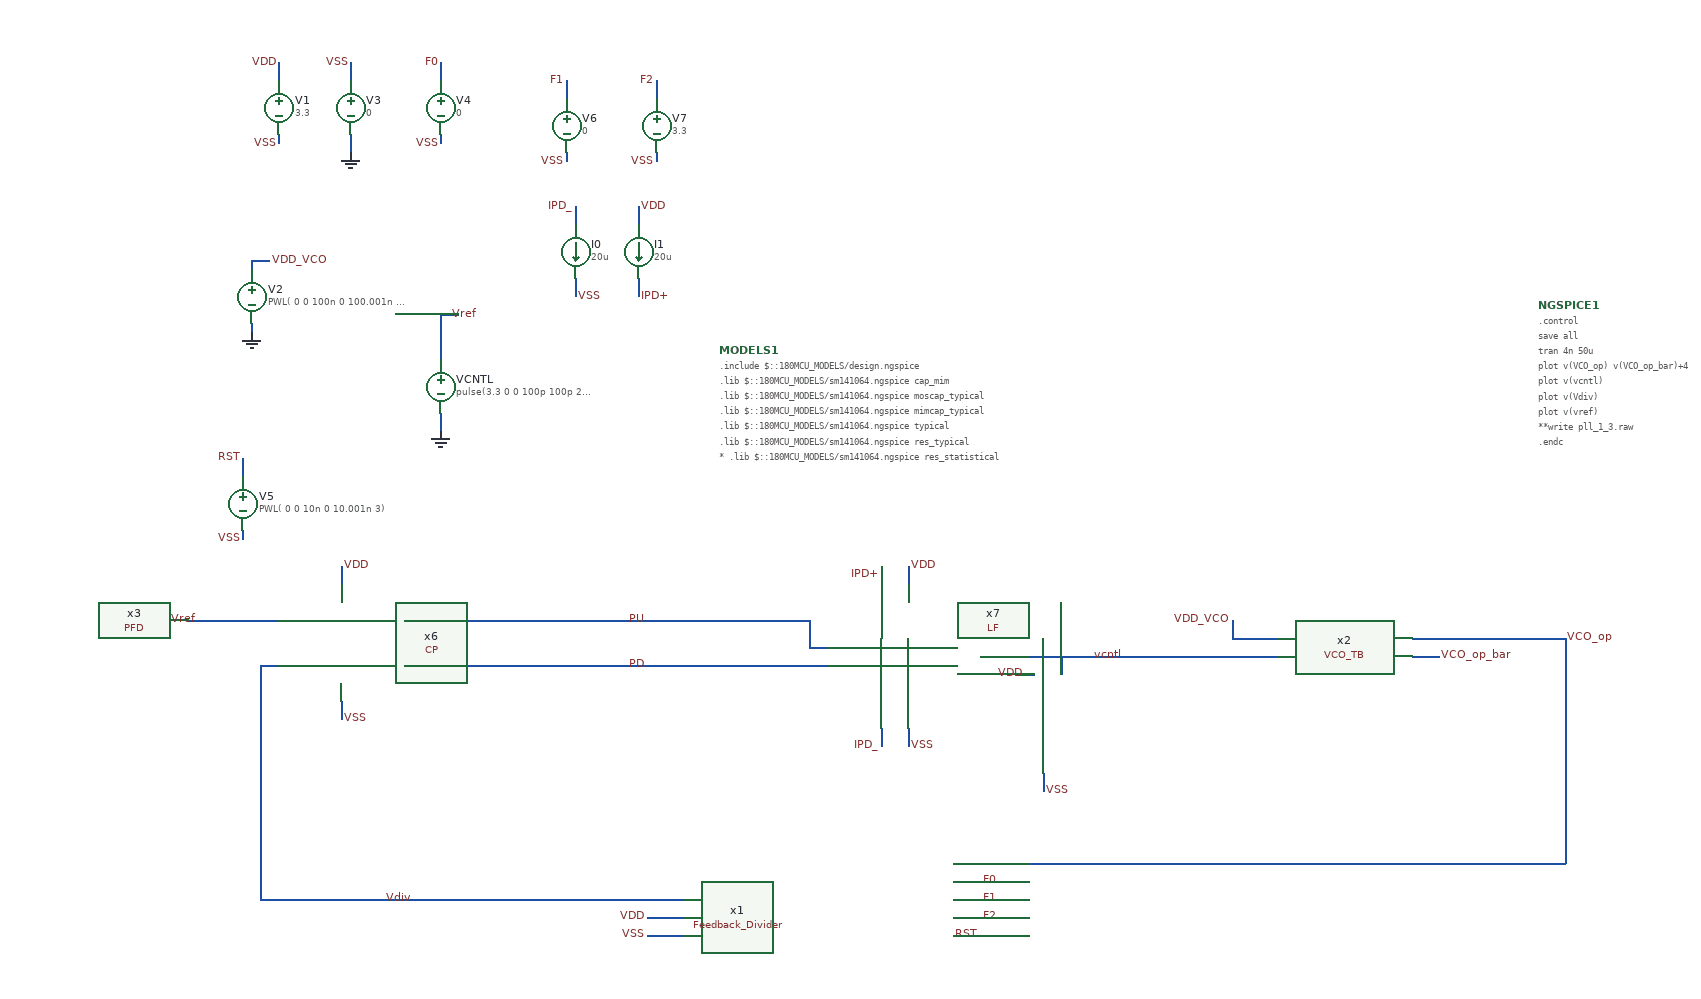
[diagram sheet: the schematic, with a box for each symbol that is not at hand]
v {xschem version=3.1.0 file_version=1.2
}
G {}
K {}
V {}
S {}
E {}
B 2 1560 -1310 2360 -1180 {flags=graph
y1=2.028
y2=5.708
ypos1=0
ypos2=2
divy=5
subdivy=1
unity=1
x1=7.92961e-08
x2=1.66523e-06
divx=5
subdivx=1


dataset=-1
unitx=1
logx=0
logy=0
color=4
node=pd}
B 2 1560 -1440 2360 -1310 {flags=graph
y1=-0.17
y2=3.5
ypos1=0
ypos2=2
divy=5
subdivy=1
unity=1
x1=7.92961e-08
x2=1.66523e-06
divx=5
subdivx=1


dataset=-1
unitx=1
logx=0
logy=0
color=4
node=pu}
B 2 1560 -1570 2360 -1440 {flags=graph
y1=-0.14
y2=3.4
ypos1=0
ypos2=2
divy=5
subdivy=1
unity=1
x1=7.92961e-08
x2=1.66523e-06
divx=5
subdivx=1
node=vdiv
color=4
dataset=-1
unitx=1
logx=0
logy=0
}
B 2 1560 -1180 2360 -1050 {flags=graph
y1=-5.3e-05
y2=0.89
ypos1=0
ypos2=2
divy=5
subdivy=1
unity=1
x1=7.92961e-08
x2=1.66523e-06
divx=5
subdivx=1


dataset=-1
unitx=1
logx=0
logy=0
color=4
node=vcntl}
B 2 1560 -1050 2360 -920 {flags=graph
y1=-0.22
y2=3.6
ypos1=0
ypos2=2
divy=5
subdivy=1
unity=1
x1=7.92961e-08
x2=1.66523e-06
divx=5
subdivx=1
node=vco_op
color=4
dataset=-1
unitx=1
logx=0
logy=0
}
B 2 1560 -920 2360 -790 {flags=graph
y1=-0.15
y2=3.5
ypos1=0
ypos2=2
divy=5
subdivy=1
unity=1
x1=7.92961e-08
x2=1.66523e-06
divx=5
subdivx=1


dataset=-1
unitx=1
logx=0
logy=0
color=4
node=vco_op_bar}
B 2 1560 -1700 2360 -1570 {flags=graph
y1=0
y2=3.3
ypos1=0
ypos2=2
divy=5
subdivy=1
unity=1
x1=7.92961e-08
x2=1.66523e-06
divx=5
subdivx=1
node=vref
color=4
dataset=-1
unitx=1
logx=0
logy=0
}
N 120 -1170 120 -1150 {
lab=VDD}
N 120 -1020 120 -1000 {
lab=VSS}
N 30 -1110 50 -1110 {
lab=Vref}
N 30 -1060 50 -1060 {
lab=Vdiv}
N 190 -1060 210 -1060 {
lab=PD}
N -50 -1110 10 -1110 {
lab=Vref}
N 10 -1110 30 -1110 {
lab=Vref}
N 210 -1110 300 -1110 {
lab=PU}
N 210 -1060 300 -1060 {
lab=PD}
N 490 -1110 640 -1110 {
lab=PU}
N 490 -1060 640 -1060 {
lab=PD}
N 30 -1060 30 -930 {
lab=Vdiv}
N 30 -830 30 -800 {
lab=Vdiv}
N 40 -800 330 -800 {
lab=Vdiv}
N 1420 -1090 1480 -1090 {
lab=VCO_op}
N 1360 -1090 1420 -1090 {
lab=VCO_op}
N 1310 -1090 1360 -1090 {
lab=VCO_op}
N 1110 -1090 1150 -1090 {
lab=VDD_VCO}
N 1310 -1070 1340 -1070 {
lab=VCO_op_bar}
N 30 -930 30 -830 {
lab=Vdiv}
N 30 -800 40 -800 {
lab=Vdiv}
N 190 -1110 210 -1110 {
lab=PU}
N 300 -1110 490 -1110 {
lab=PU}
N 300 -1060 490 -1060 {
lab=PD}
N 230 -1340 230 -1320 {
lab=GND}
N 20 -1440 20 -1430 {
lab=GND}
N 230 -1450 250 -1450 {
lab=Vref}
N 50 -1650 50 -1640 {
lab=VSS}
N 50 -1730 50 -1710 {
lab=VDD}
N 130 -1730 130 -1710 {
lab=VSS}
N 130 -1650 130 -1630 {
lab=GND}
N 1110 -1110 1110 -1090 {
lab=VDD_VCO}
N 330 -800 500 -800 {
lab=Vdiv}
N 460 -780 500 -780 {
lab=VDD}
N 460 -760 500 -760 {
lab=VSS}
N 800 -780 830 -780 {
lab=F2}
N 800 -760 830 -760 {
lab=RST}
N 830 -840 1480 -840 {
lab=VCO_op}
N 10 -1210 10 -1200 {
lab=VSS}
N 10 -1290 10 -1270 {
lab=RST}
N 1480 -1090 1480 -1070 {
lab=VCO_op}
N 990 -1070 1000 -1070 {
lab=vcntl}
N 230 -1450 230 -1400 {
lab=Vref}
N 1150 -1090 1160 -1090 {
lab=VDD_VCO}
N 1000 -1070 1160 -1070 {
lab=vcntl}
N 800 -840 820 -840 {
lab=VCO_op}
N 820 -840 830 -840 {
lab=VCO_op}
N 1480 -1070 1480 -840 {
lab=VCO_op}
N 800 -820 830 -820 {
lab=F0}
N 800 -800 830 -800 {
lab=F1}
N 20 -1510 20 -1500 {
lab=VDD_VCO}
N 20 -1510 40 -1510 {
lab=VDD_VCO}
N 370 -1630 370 -1620 {
lab=VSS}
N 370 -1710 370 -1690 {
lab=F1}
N 230 -1650 230 -1640 {
lab=VSS}
N 230 -1730 230 -1710 {
lab=F0}
N 470 -1630 470 -1620 {
lab=VSS}
N 470 -1710 470 -1690 {
lab=F2}
N 750 -1170 750 -1150 {
lab=VDD}
N 750 -990 750 -970 {
lab=VSS}
N 640 -1110 640 -1090 {
lab=PU}
N 640 -1090 640 -1080 {
lab=PU}
N 640 -1080 660 -1080 {
lab=PU}
N 640 -1060 660 -1060 {
lab=PD}
N 900 -940 900 -920 {
lab=VSS}
N 720 -1170 720 -1150 {
lab=IPD+}
N 720 -990 720 -970 {
lab=IPD_}
N 830 -1070 900 -1070 {
lab=vcntl}
N 900 -1070 990 -1070 {
lab=vcntl}
N 380 -1490 380 -1470 {
lab=VSS}
N 450 -1490 450 -1470 {
lab=IPD+}
N 380 -1570 380 -1550 {
lab=IPD_}
N 450 -1570 450 -1550 {
lab=VDD}
N 920 -1070 920 -1050 {
lab=vcntl}
N 880 -1050 890 -1050 {
lab=VDD}
N 870 -1050 880 -1050 {
lab=VDD}
C {PFD.sym} -170 -900 0 0 {name=x3}
C {devices/lab_pin.sym} 120 -1170 2 0 {name=p9 sig_type=std_logic lab=VDD}
C {devices/lab_wire.sym} 120 -1000 2 0 {name=p10 sig_type=std_logic lab=VSS}
C {devices/lab_pin.sym} -40 -1110 0 0 {name=p24 sig_type=std_logic lab=Vref
}
C {devices/lab_pin.sym} 200 -800 3 0 {name=p28 sig_type=std_logic lab=Vdiv
}
C {devices/lab_pin.sym} 1480 -1090 2 0 {name=p36 sig_type=std_logic lab=VCO_op
}
C {devices/vsource.sym} 230 -1370 0 0 {name=VCNTL value="pulse(3.3 0 0 100p 100p 250n 500n)"}
C {devices/gnd.sym} 230 -1320 0 0 {name=l2 lab=GND}
C {devices/gnd.sym} 20 -1430 0 0 {name=l1 lab=GND}
C {devices/vsource.sym} 20 -1470 0 0 {name=V2 value=" PWL( 0 0 100n 0 100.001n 3.3)"}
C {devices/code_shown.sym} 1450 -1460 0 1 {name=NGSPICE1 only_toplevel=true
value="
.control
save all
tran 4n 50u 
plot v(VCO_op) v(VCO_op_bar)+4
plot v(vcntl)
plot v(Vdiv)
plot v(vref)
**write pll_1_3.raw
.endc
"}
C {devices/vsource.sym} 50 -1680 0 0 {name=V1 value=3.3}
C {devices/vsource.sym} 130 -1680 0 0 {name=V3 value=0}
C {devices/lab_wire.sym} 130 -1730 0 0 {name=p1 sig_type=std_logic lab=VSS}
C {devices/lab_wire.sym} 50 -1640 0 0 {name=p3 sig_type=std_logic lab=VSS
}
C {devices/lab_wire.sym} 50 -1730 0 0 {name=p4 sig_type=std_logic lab=VDD}
C {devices/gnd.sym} 130 -1630 0 0 {name=l3 lab=GND}
C {devices/lab_pin.sym} 1110 -1110 0 0 {name=p2 sig_type=std_logic lab=VDD_VCO}
C {devices/lab_pin.sym} 1340 -1070 2 0 {name=p5 sig_type=std_logic lab=VCO_op_bar
}
C {devices/lab_pin.sym} 460 -780 0 0 {name=p6 sig_type=std_logic lab=VDD}
C {devices/lab_wire.sym} 460 -760 3 0 {name=p7 sig_type=std_logic lab=VSS}
C {devices/lab_pin.sym} 830 -760 3 0 {name=p8 sig_type=std_logic lab=RST}
C {devices/lab_pin.sym} 40 -1510 2 0 {name=p11 sig_type=std_logic lab=VDD_VCO}
C {devices/lab_pin.sym} 240 -1450 2 0 {name=p12 sig_type=std_logic lab=Vref
}
C {devices/lab_wire.sym} 10 -1200 0 0 {name=p13 sig_type=std_logic lab=VSS
}
C {devices/lab_wire.sym} 10 -1290 0 0 {name=p17 sig_type=std_logic lab=RST}
C {devices/vsource.sym} 10 -1240 0 0 {name=V5 value=" PWL( 0 0 10n 0 10.001n 3)"}
C {devices/lab_pin.sym} 990 -1070 1 0 {name=p14 sig_type=std_logic lab=vcntl
}
C {devices/lab_pin.sym} 460 -1110 1 0 {name=p18 sig_type=std_logic lab=PU}
C {devices/lab_pin.sym} 460 -1060 1 0 {name=p19 sig_type=std_logic lab=PD}
C {VCO_TB.sym} 1290 -960 0 0 {name=x2}
C {Feedback_Divider.sym} 650 -800 2 0 {name=x1}
C {devices/lab_pin.sym} 830 -820 2 0 {name=p20 sig_type=std_logic lab=F0}
C {devices/lab_pin.sym} 830 -800 2 0 {name=p21 sig_type=std_logic lab=F1}
C {devices/lab_pin.sym} 830 -780 2 0 {name=p22 sig_type=std_logic lab=F2}
C {devices/vsource.sym} 370 -1660 0 0 {name=V6 value=0}
C {devices/lab_wire.sym} 370 -1620 0 0 {name=p26 sig_type=std_logic lab=VSS
}
C {devices/lab_wire.sym} 370 -1710 0 0 {name=p27 sig_type=std_logic lab=F1}
C {devices/vsource.sym} 230 -1680 0 0 {name=V4 value=0}
C {devices/lab_wire.sym} 230 -1640 0 0 {name=p23 sig_type=std_logic lab=VSS
}
C {devices/lab_wire.sym} 230 -1730 0 0 {name=p25 sig_type=std_logic lab=F0}
C {devices/vsource.sym} 470 -1660 0 0 {name=V7 value=3.3}
C {devices/lab_wire.sym} 470 -1620 0 0 {name=p29 sig_type=std_logic lab=VSS
}
C {devices/lab_wire.sym} 470 -1710 0 0 {name=p30 sig_type=std_logic lab=F2}
C {devices/lab_wire.sym} 750 -970 2 0 {name=p38 sig_type=std_logic lab=VSS}
C {devices/lab_pin.sym} 750 -1170 2 0 {name=p39 sig_type=std_logic lab=VDD}
C {CP.sym} 170 -870 0 0 {name=x6}
C {LF.sym} 760 -890 0 0 {name=x7}
C {devices/lab_wire.sym} 900 -920 2 0 {name=p40 sig_type=std_logic lab=VSS}
C {devices/lab_wire.sym} 720 -1160 0 0 {name=p41 sig_type=std_logic lab=IPD+}
C {devices/lab_wire.sym} 720 -970 0 0 {name=p42 sig_type=std_logic lab=IPD_}
C {devices/isource.sym} 380 -1520 0 0 {name=I0 value=20u}
C {devices/isource.sym} 450 -1520 0 0 {name=I1 value=20u}
C {devices/lab_wire.sym} 380 -1570 0 0 {name=p15 sig_type=std_logic lab=IPD_}
C {devices/lab_wire.sym} 450 -1470 2 0 {name=p16 sig_type=std_logic lab=IPD+}
C {devices/lab_wire.sym} 380 -1470 2 0 {name=p43 sig_type=std_logic lab=VSS}
C {devices/lab_wire.sym} 450 -1570 2 0 {name=p44 sig_type=std_logic lab=VDD}
C {devices/lab_pin.sym} 880 -1050 2 1 {name=p31 sig_type=std_logic lab=VDD}
C {devices/code_shown.sym} 540 -1410 0 0 {name=MODELS1 only_toplevel=true
format="tcleval( @value )"
value="
.include $::180MCU_MODELS/design.ngspice
.lib $::180MCU_MODELS/sm141064.ngspice cap_mim
.lib $::180MCU_MODELS/sm141064.ngspice moscap_typical
.lib $::180MCU_MODELS/sm141064.ngspice mimcap_typical
.lib $::180MCU_MODELS/sm141064.ngspice typical
.lib $::180MCU_MODELS/sm141064.ngspice res_typical
* .lib $::180MCU_MODELS/sm141064.ngspice res_statistical
"}
